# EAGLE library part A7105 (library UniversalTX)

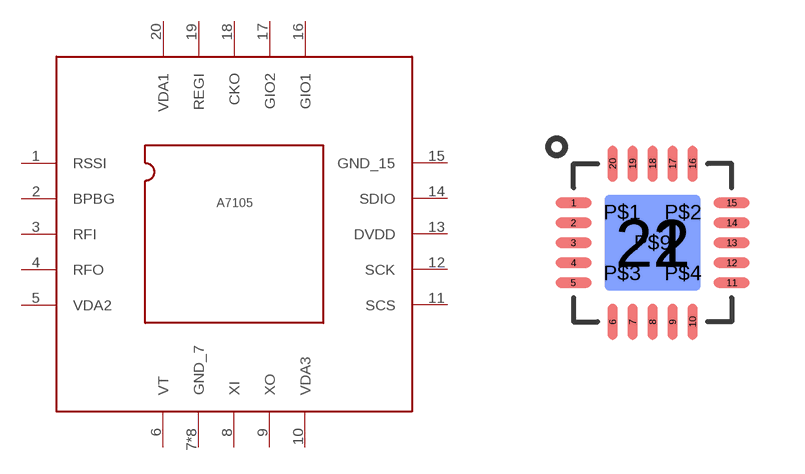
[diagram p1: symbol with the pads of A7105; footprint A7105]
Designator prefix A7105

## A7105  [A7105]
1  RSSI
2  BPBG
3  RFI
4  RFO
5  VDA2
6  VT
7  GND_7
8  XI
9  XO
10  VDA3
11  SCS
12  SCK
13  DVDD
14  SDIO
15  GND_15
16  GIO1
17  GIO2
18  CKO
19  REGI
20  VDA1
21  GND_7
22  GND_7
P$1  GND_7
P$2  GND_7
P$3  GND_7
P$4  GND_7
P$9  GND_7

## Footprint A7105 (pad centres in mm)
smd 0.9 x 0.25: 1 -1.98,1; 2 -1.98,0.5; 3 -1.98,0; 4 -1.98,-0.5; 5 -1.98,-1; 11 1.98,-1; 12 1.98,-0.5; 13 1.98,0; 14 1.98,0.5; 15 1.98,1
smd 0.25 x 0.9: 6 -1,-1.98; 7 -0.5,-1.98; 8 0,-1.98; 9 0.5,-1.98; 10 1,-1.98; 16 1,1.98; 17 0.5,1.98; 18 0,1.98; 19 -0.5,1.98; 20 -1,1.98
smd 2.4 x 2.4: 21 0,0
smd 2.4 x 2.4 bottom: 22 0,0
drill 0.33 pad 0.686: P$1 -0.762,0.762; P$2 0.762,0.762; P$3 -0.762,-0.762; P$4 0.762,-0.762; P$9 0,0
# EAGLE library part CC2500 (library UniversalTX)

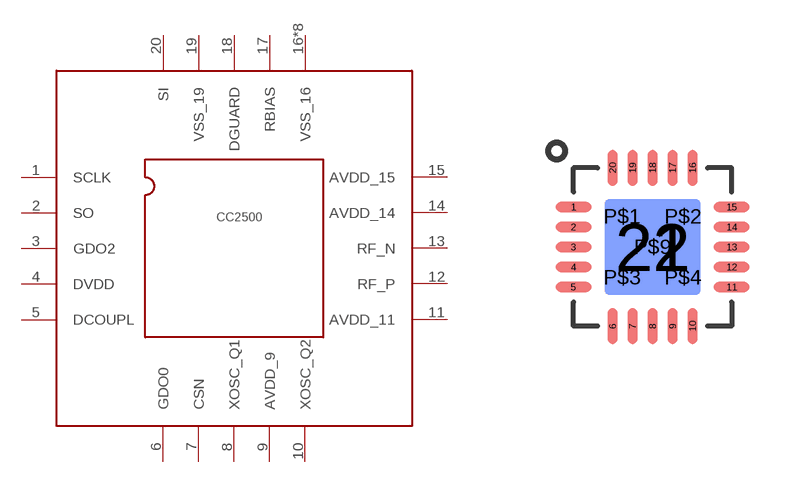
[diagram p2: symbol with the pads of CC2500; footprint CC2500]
Designator prefix -

## CC2500  [CC2500]
1  SCLK
2  SO
3  GDO2
4  DVDD
5  DCOUPL
6  GDO0
7  CSN
8  XOSC_Q1
9  AVDD_9
10  XOSC_Q2
11  AVDD_11
12  RF_P
13  RF_N
14  AVDD_14
15  AVDD_15
16  VSS_16
17  RBIAS
18  DGUARD
19  VSS_19
20  SI
21  VSS_16
22  VSS_16
P$1  VSS_16
P$2  VSS_16
P$3  VSS_16
P$4  VSS_16
P$9  VSS_16

## Footprint CC2500 (pad centres in mm)
smd 0.9 x 0.25: 1 -1.98,1; 2 -1.98,0.5; 3 -1.98,0; 4 -1.98,-0.5; 5 -1.98,-1; 11 1.98,-1; 12 1.98,-0.5; 13 1.98,0; 14 1.98,0.5; 15 1.98,1
smd 0.25 x 0.9: 6 -1,-1.98; 7 -0.5,-1.98; 8 0,-1.98; 9 0.5,-1.98; 10 1,-1.98; 16 1,1.98; 17 0.5,1.98; 18 0,1.98; 19 -0.5,1.98; 20 -1,1.98
smd 2.4 x 2.4: 21 0,0
smd 2.4 x 2.4 bottom: 22 0,0
drill 0.33 pad 0.686: P$1 -0.762,0.762; P$2 0.762,0.762; P$3 -0.762,-0.762; P$4 0.762,-0.762; P$9 0,0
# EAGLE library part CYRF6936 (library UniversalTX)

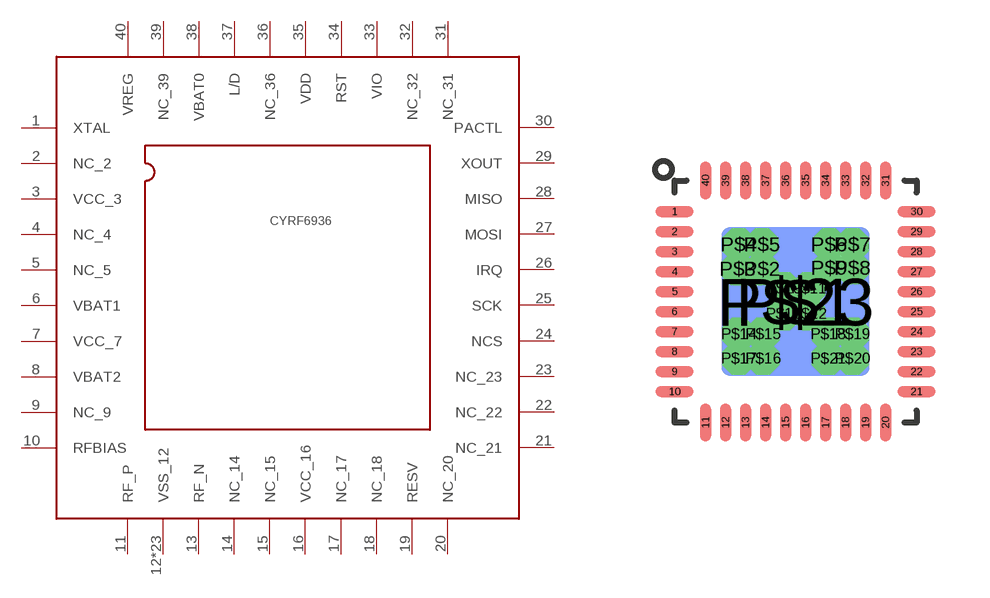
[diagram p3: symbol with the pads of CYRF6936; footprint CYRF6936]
Designator prefix -

## CYRF6936  [CYRF6936]
1  XTAL
2  NC_2
3  VCC_3
4  NC_4
5  NC_5
6  VBAT1
7  VCC_7
8  VBAT2
9  NC_9
10  RFBIAS
11  RF_P
12  VSS_12
13  RF_N
14  NC_14
15  NC_15
16  VCC_16
17  NC_17
18  NC_18
19  RESV
20  NC_20
21  NC_21
22  NC_22
23  NC_23
24  NCS
25  SCK
26  IRQ
27  MOSI
28  MISO
29  XOUT
30  PACTL
31  NC_31
32  NC_32
33  VIO
34  RST
35  VDD
36  NC_36
37  L/D
38  VBAT0
39  NC_39
40  VREG
P$1  VSS_12
P$2  VSS_12
P$3  VSS_12
P$4  VSS_12
P$5  VSS_12
P$6  VSS_12
P$7  VSS_12
P$8  VSS_12
P$9  VSS_12
P$10  VSS_12
P$11  VSS_12
P$12  VSS_12
P$13  VSS_12
P$14  VSS_12
P$15  VSS_12
P$16  VSS_12
P$17  VSS_12
P$18  VSS_12
P$19  VSS_12
P$20  VSS_12
P$21  VSS_12
P$23  VSS_12

## Footprint CYRF6936 (pad centres in mm)
smd 0.95 x 0.28: 1 -3.025,2.25; 2 -3.025,1.75; 3 -3.025,1.25; 4 -3.025,0.75; 5 -3.025,0.25; 6 -3.025,-0.25; 7 -3.025,-0.75; 8 -3.025,-1.25; 9 -3.025,-1.75; 10 -3.025,-2.25; 21 3.025,-2.25; 22 3.025,-1.75; 23 3.025,-1.25; 24 3.025,-0.75; 25 3.025,-0.25; 26 3.025,0.25; 27 3.025,0.75; 28 3.025,1.25; 29 3.025,1.75; 30 3.025,2.25
smd 0.28 x 0.95: 11 -2.25,-3.025; 12 -1.75,-3.025; 13 -1.25,-3.025; 14 -0.75,-3.025; 15 -0.25,-3.025; 16 0.25,-3.025; 17 0.75,-3.025; 18 1.25,-3.025; 19 1.75,-3.025; 20 2.25,-3.025; 31 2.25,3.025; 32 1.75,3.025; 33 1.25,3.025; 34 0.75,3.025; 35 0.25,3.025; 36 -0.25,3.025; 37 -0.75,3.025; 38 -1.25,3.025; 39 -1.75,3.025; 40 -2.25,3.025
smd 3.7 x 3.7: P$1 0,0
drill 0.305 pad 0.635 octagon: P$2 -0.838,0.813; P$3 -1.448,0.813; P$4 -1.422,1.422; P$5 -0.838,1.422; P$6 0.838,1.422; P$7 1.422,1.422; P$8 1.422,0.838; P$9 0.838,0.838; P$10 -0.305,0.33; P$11 0.33,0.33; P$12 0.33,-0.305; P$13 -0.305,-0.305; P$14 -1.422,-0.813; P$15 -0.813,-0.813; P$16 -0.813,-1.422; P$17 -1.422,-1.422; P$18 0.813,-0.813; P$19 1.422,-0.813; P$20 1.422,-1.422; P$21 0.813,-1.422
smd 3.7 x 3.7 bottom: P$23 0,0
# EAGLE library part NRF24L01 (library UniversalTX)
nRF24L01 Single chip 2.4GHz transceiver from Nordic Semiconductors.

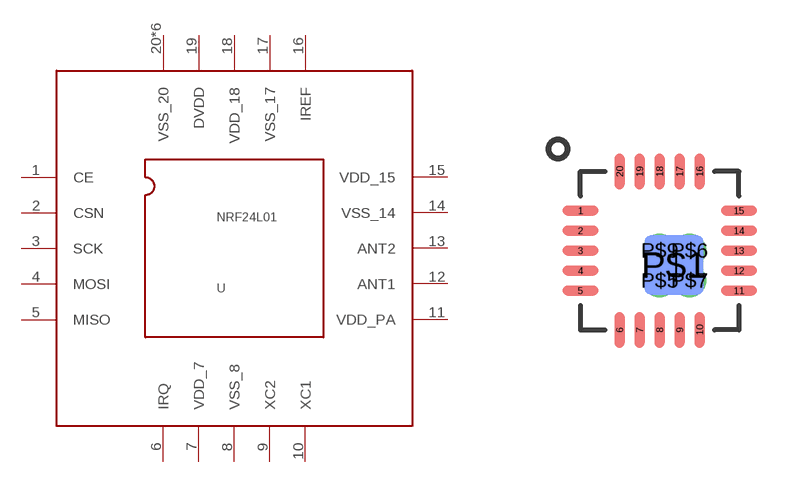
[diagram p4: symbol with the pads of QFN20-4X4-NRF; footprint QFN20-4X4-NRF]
Designator prefix -

## NRF24L01  [QFN20-4X4-NRF]
1  CE
2  CSN
3  SCK
4  MOSI
5  MISO
6  IRQ
7  VDD_7
8  VSS_8
9  XC2
10  XC1
11  VDD_PA
12  ANT1
13  ANT2
14  VSS_14
15  VDD_15
16  IREF
17  VSS_17
18  VDD_18
19  DVDD
20  VSS_20
P$1  VSS_20
P$5  VSS_20
P$6  VSS_20
P$7  VSS_20
P$9  VSS_20

## Footprint QFN20-4X4-NRF (pad centres in mm)
QFN20 4mm x 4mm package, with matt tin plating from Nordic Semiconductor.
smd 0.9 x 0.25: 1 -1.98,1; 2 -1.98,0.5; 3 -1.98,0; 4 -1.98,-0.5; 5 -1.98,-1; 11 1.98,-1; 12 1.98,-0.5; 13 1.98,0; 14 1.98,0.5; 15 1.98,1
smd 0.25 x 0.9: 6 -1,-1.98; 7 -0.5,-1.98; 8 0,-1.98; 9 0.5,-1.98; 10 1,-1.98; 16 1,1.98; 17 0.5,1.98; 18 0,1.98; 19 -0.5,1.98; 20 -1,1.98
smd 1.474 x 1.474 bottom: P$1 0.356,-0.356
drill 0.33 pad 0.61: P$5 0,-0.75; P$6 0.75,0; P$7 0.75,-0.75; P$9 0,0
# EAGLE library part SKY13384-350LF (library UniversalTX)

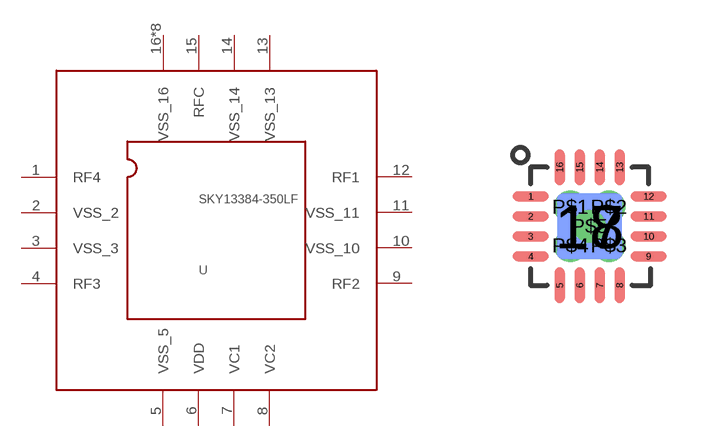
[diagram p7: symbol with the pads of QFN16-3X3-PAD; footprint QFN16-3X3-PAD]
Designator prefix -

## SKY13384-350LF  [QFN16-3X3-PAD]
1  RF4
2  VSS_2
3  VSS_3
4  RF3
5  VSS_5
6  VDD
7  VC1
8  VC2
9  RF2
10  VSS_10
11  VSS_11
12  RF1
13  VSS_13
14  VSS_14
15  RFC
16  VSS_16
17  VSS_16
18  VSS_16
P$1  VSS_16
P$2  VSS_16
P$3  VSS_16
P$4  VSS_16
P$5  VSS_16

## Footprint QFN16-3X3-PAD (pad centres in mm)
RTE (S-PQFP-N16) 3x3 mm Source: www.ti.com .. tpa6132a2 direct path stereo $.65.pdf
smd 0.9 x 0.25: 1 -1.475,0.75; 2 -1.475,0.25; 3 -1.475,-0.25; 4 -1.475,-0.75; 9 1.475,-0.75; 10 1.475,-0.25; 11 1.475,0.25; 12 1.475,0.75
smd 0.25 x 0.9: 5 -0.75,-1.475; 6 -0.25,-1.475; 7 0.25,-1.475; 8 0.75,-1.475; 13 0.75,1.475; 14 0.25,1.475; 15 -0.25,1.475; 16 -0.75,1.475
smd 1.65 x 1.65: 17 0,0
smd 1.65 x 1.65 bottom: 18 0,0
drill 0.305 pad 0.635: P$1 -0.483,0.483; P$2 0.483,0.483; P$3 0.483,-0.483; P$4 -0.483,-0.483; P$5 0,0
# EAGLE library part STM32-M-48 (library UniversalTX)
STM32F103 Medium Density 48pins

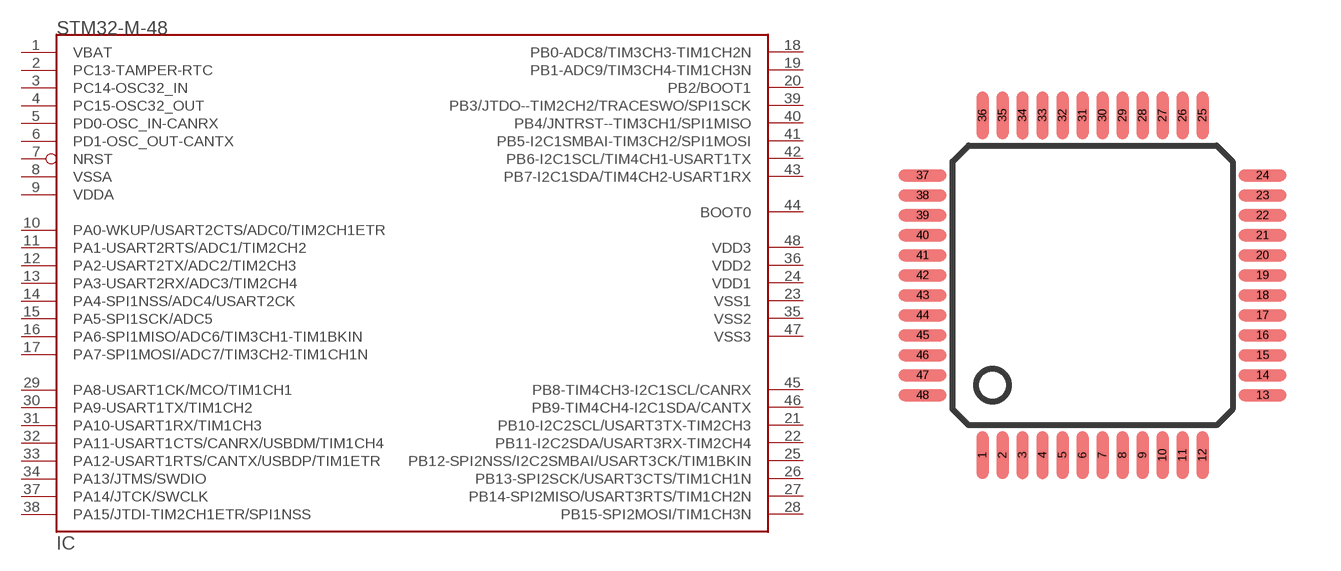
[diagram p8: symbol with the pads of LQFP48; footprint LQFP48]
Designator prefix IC

## STM32-M-48  [LQFP48]
1  VBAT  sup
2  PC13-TAMPER-RTC
3  PC14-OSC32_IN
4  PC15-OSC32_OUT
5  PD0-OSC_IN-CANRX  in
6  PD1-OSC_OUT-CANTX  out
7  NRST
8  VSSA  sup
9  VDDA  sup
10  PA0-WKUP/USART2CTS/ADC0/TIM2CH1ETR
11  PA1-USART2RTS/ADC1/TIM2CH2
12  PA2-USART2TX/ADC2/TIM2CH3
13  PA3-USART2RX/ADC3/TIM2CH4
14  PA4-SPI1NSS/ADC4/USART2CK
15  PA5-SPI1SCK/ADC5
16  PA6-SPI1MISO/ADC6/TIM3CH1-TIM1BKIN
17  PA7-SPI1MOSI/ADC7/TIM3CH2-TIM1CH1N
18  PB0-ADC8/TIM3CH3-TIM1CH2N
19  PB1-ADC9/TIM3CH4-TIM1CH3N
20  PB2/BOOT1
21  PB10-I2C2SCL/USART3TX-TIM2CH3
22  PB11-I2C2SDA/USART3RX-TIM2CH4
23  VSS1  sup
24  VDD1  sup
25  PB12-SPI2NSS/I2C2SMBAI/USART3CK/TIM1BKIN
26  PB13-SPI2SCK/USART3CTS/TIM1CH1N
27  PB14-SPI2MISO/USART3RTS/TIM1CH2N
28  PB15-SPI2MOSI/TIM1CH3N
29  PA8-USART1CK/MCO/TIM1CH1
30  PA9-USART1TX/TIM1CH2
31  PA10-USART1RX/TIM1CH3
32  PA11-USART1CTS/CANRX/USBDM/TIM1CH4
33  PA12-USART1RTS/CANTX/USBDP/TIM1ETR
34  PA13/JTMS/SWDIO
35  VSS2  sup
36  VDD2  sup
37  PA14/JTCK/SWCLK
38  PA15/JTDI-TIM2CH1ETR/SPI1NSS
39  PB3/JTDO--TIM2CH2/TRACESWO/SPI1SCK
40  PB4/JNTRST--TIM3CH1/SPI1MISO
41  PB5-I2C1SMBAI-TIM3CH2/SPI1MOSI
42  PB6-I2C1SCL/TIM4CH1-USART1TX
43  PB7-I2C1SDA/TIM4CH2-USART1RX
44  BOOT0  in
45  PB8-TIM4CH3-I2C1SCL/CANRX
46  PB9-TIM4CH4-I2C1SDA/CANTX
47  VSS3  sup
48  VDD3  sup

## Footprint LQFP48 (pad centres in mm)
Based on STM PCB layout recomendations.
smd 0.3 x 1.2: 1 -2.75,-4.25; 2 -2.25,-4.25; 3 -1.75,-4.25; 4 -1.25,-4.25; 5 -0.75,-4.25; 6 -0.25,-4.25; 7 0.25,-4.25; 8 0.75,-4.25; 9 1.25,-4.25; 10 1.75,-4.25; 11 2.25,-4.25; 12 2.75,-4.25; 25 2.75,4.25; 26 2.25,4.25; 27 1.75,4.25; 28 1.25,4.25; 29 0.75,4.25; 30 0.25,4.25; 31 -0.25,4.25; 32 -0.75,4.25; 33 -1.25,4.25; 34 -1.75,4.25; 35 -2.25,4.25; 36 -2.75,4.25
smd 1.2 x 0.3: 13 4.25,-2.75; 14 4.25,-2.25; 15 4.25,-1.75; 16 4.25,-1.25; 17 4.25,-0.75; 18 4.25,-0.25; 19 4.25,0.25; 20 4.25,0.75; 21 4.25,1.25; 22 4.25,1.75; 23 4.25,2.25; 24 4.25,2.75; 37 -4.25,2.75; 38 -4.25,2.25; 39 -4.25,1.75; 40 -4.25,1.25; 41 -4.25,0.75; 42 -4.25,0.25; 43 -4.25,-0.25; 44 -4.25,-0.75; 45 -4.25,-1.25; 46 -4.25,-1.75; 47 -4.25,-2.25; 48 -4.25,-2.75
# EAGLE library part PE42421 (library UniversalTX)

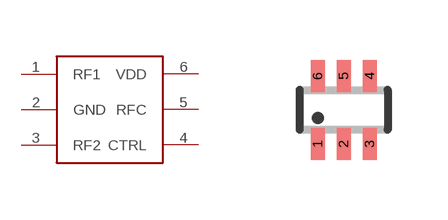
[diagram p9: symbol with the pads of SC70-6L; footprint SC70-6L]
Designator prefix -

## PE42421  [SC70-6L]
1  RF1
2  GND
3  RF2
4  CTRL
5  RFC
6  VDD

## Footprint SC70-6L (pad centres in mm)
SC-70 Package
smd 0.35 x 0.8: 1 -0.65,-0.85; 2 0,-0.85; 3 0.65,-0.85; 4 0.65,0.85; 5 0,0.85; 6 -0.65,0.85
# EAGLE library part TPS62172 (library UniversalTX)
Texas Instruments TPS62172 3-17V 0.5A Step-Down Converter with DCS control. Available in adjustable and fixed output voltage versions. Is packaged in an 8-pin WSON package measuring 2 Ã— 2 mm (DSG). See a 3.3V fixed output version of this chip in action on the Electric Imp Breakout Board. Datasheet

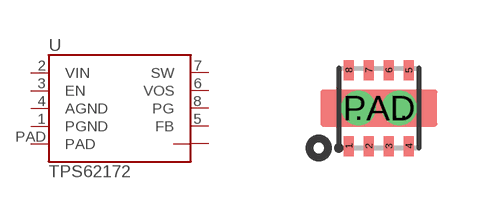
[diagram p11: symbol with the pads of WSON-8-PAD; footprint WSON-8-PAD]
Designator prefix U

## TPS62172 (PROD_ID: IC-11307)  [WSON-8-PAD]
1  PGND
2  VIN
3  EN
4  AGND
5  FB
6  VOS
7  SW
8  PG
.  .  pas
..  ..  pas
PAD  PAD  pas

## Footprint WSON-8-PAD (pad centres in mm)
smd 0.25 x 0.5: 1 -0.75,-0.95; 2 -0.25,-0.95; 3 0.25,-0.95; 4 0.75,-0.95; 5 0.75,0.95; 6 0.25,0.95; 7 -0.25,0.95; 8 -0.75,0.95
drill 0.356 pad 0.61: . -0.508,0; .. 0.508,0
smd 1.6 x 0.9: PAD 0,0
